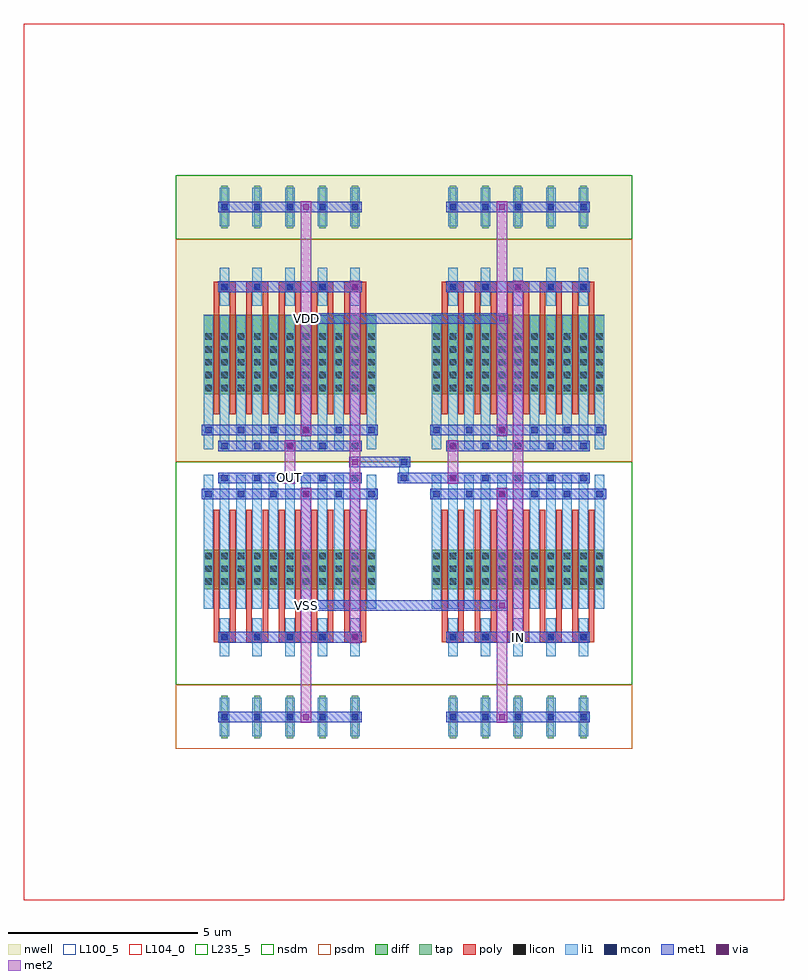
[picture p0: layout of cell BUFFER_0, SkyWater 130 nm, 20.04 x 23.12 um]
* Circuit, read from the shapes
.subckt BUFFER_0 IN OUT VDD VSS
XM1 OUT n1 VSS VSS sky130_fd_pr__nfet_01v8 w=1.05 l=0.15 m=10
XM2 n1 IN VSS VSS sky130_fd_pr__nfet_01v8 w=1.05 l=0.15 m=10
XM3 OUT n1 VDD VDD sky130_fd_pr__pfet_01v8 w=2.1 l=0.15 m=10
XM4 n1 IN VDD VDD sky130_fd_pr__pfet_01v8 w=2.1 l=0.15 m=10
.ends

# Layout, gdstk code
from math import pi, radians
import gdstk
lib = gdstk.Library(unit=1e-6, precision=1e-09)
def R(c, l, rs):  # rectangles x0, y0, x1, y1
    for r in rs: c.add(gdstk.rectangle(r[:2], r[2:], *l))
def A(c, l, x, y, w, h, nx, ny, dx, dy):  # array of equal rectangles
    R(c, l, [(x+i*dx, y+j*dy, x+i*dx+w, y+j*dy+h) for i in range(nx) for j in range(ny)])
def P(c, l, *ps):  # polygons
    for p in ps: c.add(gdstk.Polygon(p, *l))
nwell = (64, 20)
diff = (65, 20)
tap = (65, 44)
poly = (66, 20)
licon = (66, 44)
li1 = (67, 20)
mcon = (67, 44)
met1 = (68, 20)
via = (68, 44)
met2 = (69, 20)
nsdm = (93, 44)
psdm = (94, 20)
L100_5 = (100, 5)
L104_0 = (104, 0)
L235_5 = (235, 5)

nmos_s_29520189_x5_y1_16 = lib.new_cell('NMOS_S_29520189_X5_Y1_1676610624_1676610624')
R(nmos_s_29520189_x5_y1_16, diff, [(0.735,2.31,5.285,3.36)])
A(nmos_s_29520189_x5_y1_16, tap, 1.205, 6.16, 0.17, 1.12, 5, 1, 0.86, 0)
A(nmos_s_29520189_x5_y1_16, poly, 1, 1.26, 0.15, 3.36, 10, 1, 0.43, 0)
A(nmos_s_29520189_x5_y1_16, poly, 1, 4.485, 0.58, 0.27, 5, 1, 0.86, 0)
A(nmos_s_29520189_x5_y1_16, licon, 0.775, 2.39, 0.17, 0.17, 3, 3, 0.43, 0.34)
A(nmos_s_29520189_x5_y1_16, licon, 1.635, 2.39, 0.17, 0.17, 3, 3, 0.43, 0.34)
A(nmos_s_29520189_x5_y1_16, licon, 2.495, 2.39, 0.17, 0.17, 3, 3, 0.43, 0.34)
A(nmos_s_29520189_x5_y1_16, licon, 3.355, 2.39, 0.17, 0.17, 3, 3, 0.43, 0.34)
A(nmos_s_29520189_x5_y1_16, licon, 4.215, 2.39, 0.17, 0.17, 3, 3, 0.43, 0.34)
A(nmos_s_29520189_x5_y1_16, licon, 1.205, 4.535, 0.17, 0.17, 5, 2, 0.86, 2.1)
A(nmos_s_29520189_x5_y1_16, li1, 0.735, 0.335, 0.25, 3.53, 11, 1, 0.43, 0)
A(nmos_s_29520189_x5_y1_16, li1, 1.165, 4.115, 0.25, 1.01, 5, 2, 0.86, 2.1)
A(nmos_s_29520189_x5_y1_16, mcon, 1.205, 0.335, 0.17, 0.17, 5, 2, 0.86, 4.2)
A(nmos_s_29520189_x5_y1_16, mcon, 0.775, 0.755, 0.17, 0.17, 6, 1, 0.86, 0)
A(nmos_s_29520189_x5_y1_16, mcon, 1.205, 6.635, 0.17, 0.17, 5, 1, 0.86, 0)
R(nmos_s_29520189_x5_y1_16, met1, [(1.12,0.28,4.9,0.56), (0.69,0.7,5.33,0.98), (1.12,4.48,4.9,4.76), (1.12,6.58,4.9,6.86)])
R(nmos_s_29520189_x5_y1_16, via, [(3.365,0.765,3.515,0.915), (3.365,6.645,3.515,6.795)])
R(nmos_s_29520189_x5_y1_16, met2, [(3.3,0.68,3.58,6.88)])
R(nmos_s_29520189_x5_y1_16, nsdm, [(0,0,6.02,5.88)])
R(nmos_s_29520189_x5_y1_16, psdm, [(0,5.88,6.02,7.56)])
R(nmos_s_29520189_x5_y1_16, L100_5, [(0,0,6.02,7.56)])

pmos_s_61174647_x5_y1_16 = lib.new_cell('PMOS_S_61174647_X5_Y1_1676610625_1676610624')
R(pmos_s_61174647_x5_y1_16, nwell, [(0,0,6.02,7.56)])
R(pmos_s_61174647_x5_y1_16, diff, [(0.735,1.785,5.285,3.885)])
A(pmos_s_61174647_x5_y1_16, tap, 1.205, 6.16, 0.17, 1.12, 5, 1, 0.86, 0)
A(pmos_s_61174647_x5_y1_16, poly, 1, 1.26, 0.15, 3.36, 10, 1, 0.43, 0)
A(pmos_s_61174647_x5_y1_16, poly, 1, 4.485, 0.58, 0.27, 5, 1, 0.86, 0)
A(pmos_s_61174647_x5_y1_16, licon, 0.775, 1.865, 0.17, 0.17, 3, 5, 0.43, 0.34)
A(pmos_s_61174647_x5_y1_16, licon, 1.635, 1.865, 0.17, 0.17, 3, 5, 0.43, 0.34)
A(pmos_s_61174647_x5_y1_16, licon, 2.495, 1.865, 0.17, 0.17, 3, 5, 0.43, 0.34)
A(pmos_s_61174647_x5_y1_16, licon, 3.355, 1.865, 0.17, 0.17, 3, 5, 0.43, 0.34)
A(pmos_s_61174647_x5_y1_16, licon, 4.215, 1.865, 0.17, 0.17, 3, 5, 0.43, 0.34)
A(pmos_s_61174647_x5_y1_16, licon, 1.205, 4.535, 0.17, 0.17, 5, 2, 0.86, 2.1)
A(pmos_s_61174647_x5_y1_16, li1, 0.735, 0.335, 0.25, 3.53, 11, 1, 0.43, 0)
A(pmos_s_61174647_x5_y1_16, li1, 1.165, 4.115, 0.25, 1.01, 5, 2, 0.86, 2.1)
A(pmos_s_61174647_x5_y1_16, mcon, 1.205, 0.335, 0.17, 0.17, 5, 2, 0.86, 4.2)
A(pmos_s_61174647_x5_y1_16, mcon, 0.775, 0.755, 0.17, 0.17, 6, 1, 0.86, 0)
A(pmos_s_61174647_x5_y1_16, mcon, 1.205, 6.635, 0.17, 0.17, 5, 1, 0.86, 0)
R(pmos_s_61174647_x5_y1_16, met1, [(1.12,0.28,4.9,0.56), (0.69,0.7,5.33,0.98), (1.12,4.48,4.9,4.76), (1.12,6.58,4.9,6.86)])
R(pmos_s_61174647_x5_y1_16, via, [(3.365,0.765,3.515,0.915), (3.365,6.645,3.515,6.795)])
R(pmos_s_61174647_x5_y1_16, met2, [(3.3,0.68,3.58,6.88)])
R(pmos_s_61174647_x5_y1_16, nsdm, [(0,5.88,6.02,7.56)])
R(pmos_s_61174647_x5_y1_16, psdm, [(0,0,6.02,5.88)])
R(pmos_s_61174647_x5_y1_16, L100_5, [(0,0,6.02,7.56)])

stage2_inv_15241980_0_0_ = lib.new_cell('STAGE2_INV_15241980_0_0_1676610624')
R(stage2_inv_15241980_0_0_, li1, [(5.895,7.055,6.145,7.225), (5.895,7.055,6.145,7.225), (5.895,7.055,6.145,7.225), (5.895,7.055,6.145,7.225), (5.895,7.14,6.145,7.56), (5.895,7.475,6.145,7.645), (5.895,7.475,6.145,7.645), (5.895,7.475,6.145,7.645), (5.895,7.475,6.145,7.645)])
R(stage2_inv_15241980_0_0_, mcon, [(5.935,7.055,6.105,7.225), (5.935,7.055,6.105,7.225), (5.935,7.055,6.105,7.225), (5.935,7.055,6.105,7.225), (5.935,7.475,6.105,7.645), (5.935,7.475,6.105,7.645), (5.935,7.475,6.105,7.645), (5.935,7.475,6.105,7.645)])
R(stage2_inv_15241980_0_0_, met1, [(4.57,2.8,4.89,3.08), (4.57,2.8,4.89,3.08), (4.57,2.8,4.89,3.08), (4.57,2.8,4.89,3.08), (4.57,2.8,4.89,3.08), (4.57,2.8,4.89,3.08), (8.87,2.8,9.19,3.08), (8.87,2.8,9.19,3.08), (3.28,3.64,3.6,3.92), (3.28,3.64,3.6,3.92), (3.44,3.64,8.6,3.92), (8.44,3.64,8.76,3.92), (8.44,3.64,8.76,3.92), (2.85,7,3.17,7.28), (2.85,7,3.17,7.28), (5.85,7,6.19,7.28), (5.85,7,6.19,7.28), (5.85,7,6.19,7.28), (5.85,7,6.19,7.28), (6.02,7,7.31,7.28), (7.15,7,7.47,7.28), (7.15,7,7.47,7.28), (4.57,7.42,4.89,7.7), (4.57,7.42,4.89,7.7), (4.57,7.42,4.89,7.7), (4.57,7.42,4.89,7.7), (4.73,7.42,6.02,7.7), (5.85,7.42,6.19,7.7), (5.85,7.42,6.19,7.7), (5.85,7.42,6.19,7.7), (5.85,7.42,6.19,7.7), (2.85,7.84,3.17,8.12), (2.85,7.84,3.17,8.12), (7.15,7.84,7.47,8.12), (7.15,7.84,7.47,8.12), (3.28,11.2,3.6,11.48), (3.28,11.2,3.6,11.48), (3.44,11.2,8.6,11.48), (8.44,11.2,8.76,11.48), (8.44,11.2,8.76,11.48), (4.57,12.04,4.89,12.32), (4.57,12.04,4.89,12.32), (4.57,12.04,4.89,12.32), (4.57,12.04,4.89,12.32), (4.57,12.04,4.89,12.32), (4.57,12.04,4.89,12.32), (8.87,12.04,9.19,12.32), (8.87,12.04,9.19,12.32)])
P(stage2_inv_15241980_0_0_, met1, [(0,0),(0,0),(0,0),(0,0)],
  [(0,0),(0,0),(0,0),(0,0)],
  [(0,0),(0,0),(0,0),(0,0)],
  [(0,0),(0,0),(0,0),(0,0)],
  [(0,0),(0,0),(0,0),(0,0)],
  [(0,0),(0,0),(0,0),(0,0)],
  [(0,0),(0,0),(0,0),(0,0)],
  [(0,0),(0,0),(0,0),(0,0)])
R(stage2_inv_15241980_0_0_, via, [(4.655,2.865,4.805,3.015), (4.655,2.865,4.805,3.015), (4.655,2.865,4.805,3.015), (4.655,2.865,4.805,3.015), (4.655,2.865,4.805,3.015), (4.655,2.865,4.805,3.015), (8.955,2.865,9.105,3.015), (8.955,2.865,9.105,3.015), (3.365,3.705,3.515,3.855), (3.365,3.705,3.515,3.855), (8.525,3.705,8.675,3.855), (8.525,3.705,8.675,3.855), (2.935,7.065,3.085,7.215), (2.935,7.065,3.085,7.215), (7.235,7.065,7.385,7.215), (7.235,7.065,7.385,7.215), (4.655,7.485,4.805,7.635), (4.655,7.485,4.805,7.635), (4.655,7.485,4.805,7.635), (4.655,7.485,4.805,7.635), (2.935,7.905,3.085,8.055), (2.935,7.905,3.085,8.055), (7.235,7.905,7.385,8.055), (7.235,7.905,7.385,8.055), (3.365,11.265,3.515,11.415), (3.365,11.265,3.515,11.415), (8.525,11.265,8.675,11.415), (8.525,11.265,8.675,11.415), (4.655,12.105,4.805,12.255), (4.655,12.105,4.805,12.255), (4.655,12.105,4.805,12.255), (4.655,12.105,4.805,12.255), (4.655,12.105,4.805,12.255), (4.655,12.105,4.805,12.255), (8.955,12.105,9.105,12.255), (8.955,12.105,9.105,12.255)])
R(stage2_inv_15241980_0_0_, met2, [(4.59,2.78,4.87,3.1), (4.59,2.78,4.87,3.1), (4.59,2.78,4.87,3.1), (4.59,2.78,4.87,3.1), (4.59,2.78,4.87,3.1), (4.59,2.78,4.87,3.1), (8.89,2.78,9.17,3.1), (8.89,2.78,9.17,3.1), (4.59,2.94,4.87,12.18), (8.89,2.94,9.17,12.18), (3.3,3.62,3.58,3.94), (3.3,3.62,3.58,3.94), (8.46,3.62,8.74,3.94), (8.46,3.62,8.74,3.94), (2.87,6.98,3.15,7.3), (2.87,6.98,3.15,7.3), (7.17,6.98,7.45,7.3), (7.17,6.98,7.45,7.3), (2.87,7.14,3.15,7.98), (7.17,7.14,7.45,7.98), (4.59,7.4,4.87,7.72), (4.59,7.4,4.87,7.72), (4.59,7.4,4.87,7.72), (4.59,7.4,4.87,7.72), (2.87,7.82,3.15,8.14), (2.87,7.82,3.15,8.14), (7.17,7.82,7.45,8.14), (7.17,7.82,7.45,8.14), (3.3,11.18,3.58,11.5), (3.3,11.18,3.58,11.5), (8.46,11.18,8.74,11.5), (8.46,11.18,8.74,11.5), (4.59,12.02,4.87,12.34), (4.59,12.02,4.87,12.34), (4.59,12.02,4.87,12.34), (4.59,12.02,4.87,12.34), (4.59,12.02,4.87,12.34), (4.59,12.02,4.87,12.34), (8.89,12.02,9.17,12.34), (8.89,12.02,9.17,12.34)])
P(stage2_inv_15241980_0_0_, met2, [(0,0),(0,0),(0,0),(0,0)],
  [(0,0),(0,0),(0,0),(0,0)],
  [(0,0),(0,0),(0,0),(0,0)],
  [(0,0),(0,0),(0,0),(0,0)])
R(stage2_inv_15241980_0_0_, L235_5, [(0,0,12.04,15.12)])
stage2_inv_15241980_0_0_.add(gdstk.Reference(nmos_s_29520189_x5_y1_16, (12.04,7.56), rotation=pi))
stage2_inv_15241980_0_0_.add(gdstk.Reference(nmos_s_29520189_x5_y1_16, (0,7.56), x_reflection=True))
stage2_inv_15241980_0_0_.add(gdstk.Reference(pmos_s_61174647_x5_y1_16, (12.04,7.56), rotation=pi, x_reflection=True))
stage2_inv_15241980_0_0_.add(gdstk.Reference(pmos_s_61174647_x5_y1_16, (0,7.56)))

buffer_0 = lib.new_cell('BUFFER_0')
P(buffer_0, met1, [(0,0),(0,0),(0,0),(0,0)],
  [(0,0),(0,0),(0,0),(0,0)],
  [(0,0),(0,0),(0,0),(0,0)],
  [(0,0),(0,0),(0,0),(0,0)],
  [(0,0),(0,0),(0,0),(0,0)],
  [(0,0),(0,0),(0,0),(0,0)],
  [(0,0),(0,0),(0,0),(0,0)],
  [(0,0),(0,0),(0,0),(0,0)],
  [(0,0),(0,0),(0,0),(0,0)],
  [(0,0),(0,0),(0,0),(0,0)],
  [(0,0),(0,0),(0,0),(0,0)],
  [(0,0),(0,0),(0,0),(0,0)])
P(buffer_0, met2, [(0,0),(0,0),(0,0),(0,0)],
  [(0,0),(0,0),(0,0),(0,0)],
  [(0,0),(0,0),(0,0),(0,0)],
  [(0,0),(0,0),(0,0),(0,0)],
  [(0,0),(0,0),(0,0),(0,0)],
  [(0,0),(0,0),(0,0),(0,0)],
  [(0,0),(0,0),(0,0),(0,0)],
  [(0,0),(0,0),(0,0),(0,0)],
  [(0,0),(0,0),(0,0),(0,0)],
  [(0,0),(0,0),(0,0),(0,0)],
  [(0,0),(0,0),(0,0),(0,0)],
  [(0,0),(0,0),(0,0),(0,0)])
R(buffer_0, L104_0, [(-4,-4,16.04,19.12)])
R(buffer_0, L235_5, [(0,0,12.04,15.12)])
buffer_0.add(gdstk.Reference(stage2_inv_15241980_0_0_, (0,0)))
buffer_0.add(gdstk.Label('VSS', (3.44,3.78), layer=69, texttype=5))
buffer_0.add(gdstk.Label('VDD', (3.44,11.34), layer=69, texttype=5))
buffer_0.add(gdstk.Label('IN', (9.03,2.94), layer=68, texttype=5))
buffer_0.add(gdstk.Label('OUT', (3.01,7.14), layer=68, texttype=5))

lib.write_gds('BUFFER_0.gds')
